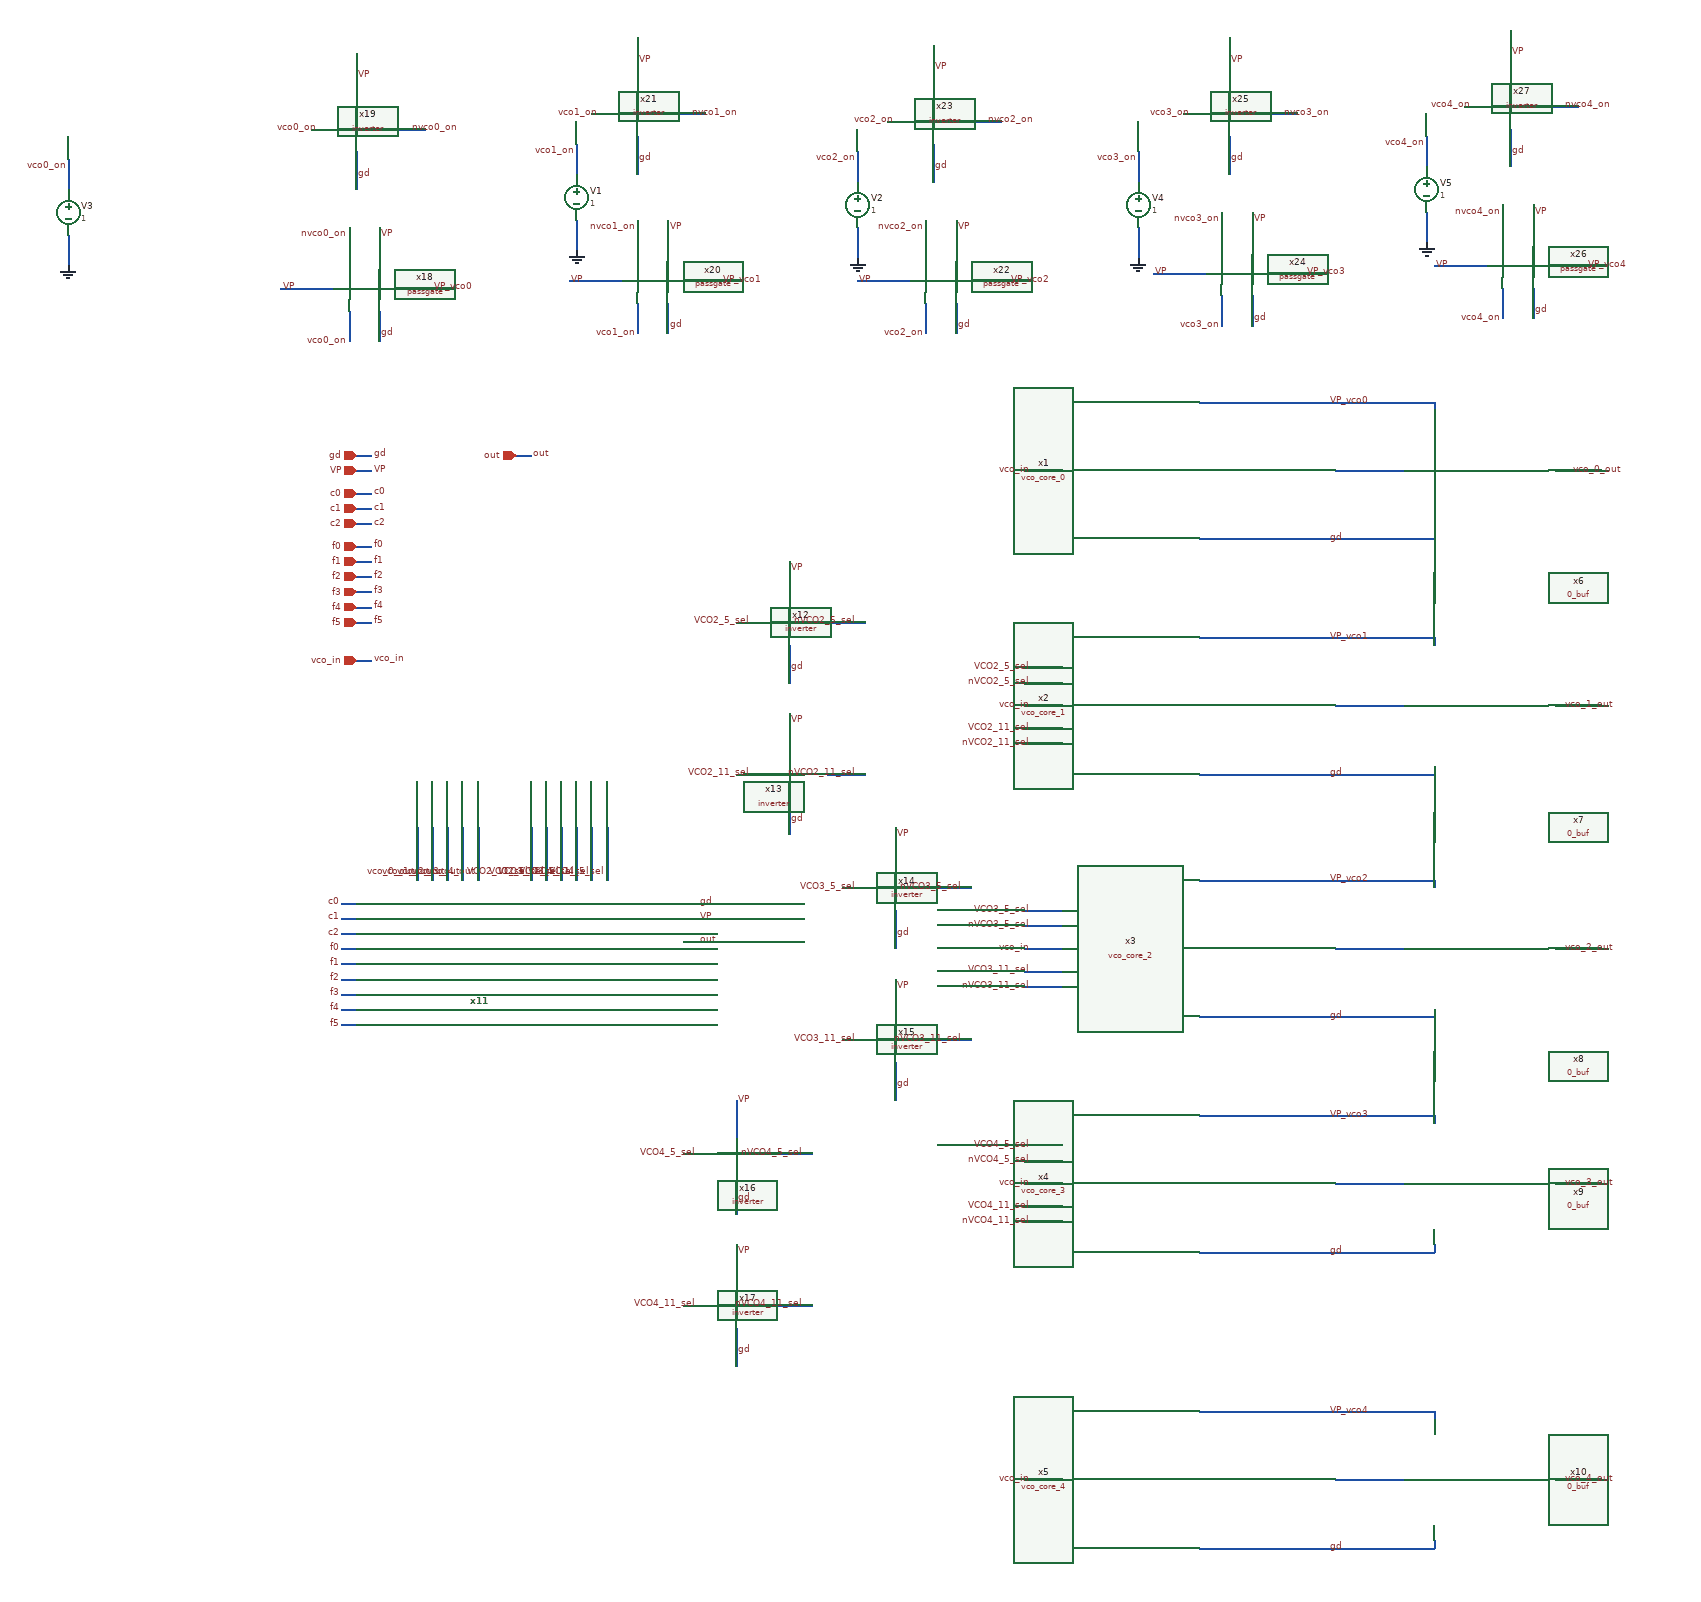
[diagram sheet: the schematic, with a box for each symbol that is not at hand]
v {xschem version=3.4.8RC file_version=1.3}
G {}
K {}
V {}
S {}
F {}
E {}
N 230 -210 320 -210 {lab=#net1}
N 230 100 320 100 {lab=#net2}
N 230 420 320 420 {lab=#net3}
N 230 730 320 730 {lab=#net4}
N 230 1120 320 1120 {lab=#net5}
N 520 -210 580 -210 {lab=vco_0_out}
N 520 100 580 100 {lab=vco_1_out}
N 520 420 580 420 {lab=vco_2_out}
N 520 730 580 730 {lab=vco_3_out}
N 520 1120 580 1120 {lab=vco_4_out}
N -1060 -230 -1040 -230 {lab=gd}
N -1060 -210 -1040 -210 {lab=VP}
N -1060 -160 -1040 -160 {lab=c1}
N -1060 -140 -1040 -140 {lab=c2}
N -1060 -110 -1040 -110 {lab=f0}
N -1060 -90 -1040 -90 {lab=f1}
N -1060 -180 -1040 -180 {lab=c0}
N -1060 -70 -1040 -70 {lab=f2}
N -1060 -50 -1040 -50 {lab=f3}
N -1060 -30 -1040 -30 {lab=f4}
N -1060 -10 -1040 -10 {lab=f5}
N -630 360 -610 360 {lab=gd}
N -630 380 -610 380 {lab=VP}
N -850 -230 -830 -230 {lab=out}
N -630 410 -610 410 {lab=out}
N 50 -120 360 -120 {lab=gd}
N 360 -130 360 -120 {lab=gd}
N 50 190 360 190 {lab=gd}
N 360 180 360 190 {lab=gd}
N 50 510 360 510 {lab=gd}
N 360 500 360 510 {lab=gd}
N 50 820 360 820 {lab=gd}
N 360 810 360 820 {lab=gd}
N 50 1210 360 1210 {lab=gd}
N 360 1200 360 1210 {lab=gd}
N 50 1030 360 1030 {lab=VP_vco4}
N 360 1030 360 1040 {lab=VP_vco4}
N 50 640 360 640 {lab=VP_vco3}
N 360 640 360 650 {lab=VP_vco3}
N 50 330 360 330 {lab=VP_vco2}
N 360 330 360 340 {lab=VP_vco2}
N 50 10 360 10 {lab=VP_vco1}
N 360 10 360 20 {lab=VP_vco1}
N 50 -300 360 -300 {lab=VP_vco0}
N 360 -300 360 -290 {lab=VP_vco0}
N -180 50 -130 50 {lab=VCO2_5_sel}
N -180 130 -130 130 {lab=VCO2_11_sel}
N -180 1120 -130 1120 {lab=vco_in}
N -180 -210 -130 -210 {lab=vco_in}
N -830 260 -830 330 {lab=VCO2_11_sel}
N -810 260 -810 330 {lab=VCO2_5_sel}
N -790 260 -790 330 {lab=VCO3_11_sel}
N -770 260 -770 330 {lab=VCO3_5_sel}
N -750 260 -750 330 {lab=VCO4_11_sel}
N -730 260 -730 330 {lab=VCO4_5_sel}
N -980 260 -980 330 {lab=vco_0_out}
N -960 260 -960 330 {lab=vco_1_out}
N -940 260 -940 330 {lab=vco_2_out}
N -920 260 -920 330 {lab=vco_3_out}
N -900 260 -900 330 {lab=vco_4_out}
N -1080 380 -1060 380 {lab=c1}
N -1080 400 -1060 400 {lab=c2}
N -1080 420 -1060 420 {lab=f0}
N -1080 440 -1060 440 {lab=f1}
N -1080 360 -1060 360 {lab=c0}
N -1080 460 -1060 460 {lab=f2}
N -1080 480 -1060 480 {lab=f3}
N -1080 500 -1060 500 {lab=f4}
N -1080 520 -1060 520 {lab=f5}
N -1060 40 -1040 40 {lab=vco_in}
N -180 100 -130 100 {lab=vco_in}
N -490 -90 -490 -40 {lab=VP}
N -490 20 -490 70 {lab=gd}
N -440 -10 -390 -10 {lab=nVCO2_5_sel}
N -560 -10 -510 -10 {lab=VCO2_5_sel}
N -180 70 -130 70 {lab=nVCO2_5_sel}
N -490 110 -490 160 {lab=VP}
N -490 220 -490 270 {lab=gd}
N -440 190 -390 190 {lab=nVCO2_11_sel}
N -560 190 -510 190 {lab=VCO2_11_sel}
N -180 150 -130 150 {lab=nVCO2_11_sel}
N -180 370 -130 370 {lab=VCO3_5_sel}
N -180 450 -130 450 {lab=VCO3_11_sel}
N -180 420 -130 420 {lab=vco_in}
N -180 390 -130 390 {lab=nVCO3_5_sel}
N -180 470 -130 470 {lab=nVCO3_11_sel}
N -350 260 -350 310 {lab=VP}
N -350 370 -350 420 {lab=gd}
N -300 340 -250 340 {lab=nVCO3_5_sel}
N -420 340 -370 340 {lab=VCO3_5_sel}
N -350 460 -350 510 {lab=VP}
N -350 570 -350 620 {lab=gd}
N -300 540 -250 540 {lab=nVCO3_11_sel}
N -420 540 -370 540 {lab=VCO3_11_sel}
N -180 680 -130 680 {lab=VCO4_5_sel}
N -180 760 -130 760 {lab=VCO4_11_sel}
N -180 730 -130 730 {lab=vco_in}
N -180 700 -130 700 {lab=nVCO4_5_sel}
N -180 780 -130 780 {lab=nVCO4_11_sel}
N -560 720 -560 770 {lab=gd}
N -510 690 -460 690 {lab=nVCO4_5_sel}
N -630 690 -580 690 {lab=VCO4_5_sel}
N -560 810 -560 860 {lab=VP}
N -560 920 -560 970 {lab=gd}
N -510 890 -460 890 {lab=nVCO4_11_sel}
N -630 890 -580 890 {lab=VCO4_11_sel}
N -560 620 -560 670 {lab=VP}
N -1160 -450 -1090 -450 {lab=VP}
N -1010 -450 -930 -450 {lab=VP_vco0}
N -1120 -660 -1080 -660 {lab=vco0_on}
N -1060 -630 -1060 -580 {lab=gd}
N -1060 -760 -1060 -690 {lab=VP}
N -1010 -660 -970 -660 {lab=nvco0_on}
N -1070 -420 -1070 -380 {lab=vco0_on}
N -1070 -530 -1070 -480 {lab=nvco0_on}
N -1030 -530 -1030 -480 {lab=VP}
N -1030 -420 -1030 -380 {lab=gd}
N -780 -460 -710 -460 {lab=VP}
N -630 -460 -550 -460 {lab=VP_vco1}
N -750 -680 -710 -680 {lab=vco1_on}
N -690 -650 -690 -600 {lab=gd}
N -690 -780 -690 -710 {lab=VP}
N -640 -680 -600 -680 {lab=nvco1_on}
N -690 -430 -690 -390 {lab=vco1_on}
N -690 -540 -690 -490 {lab=nvco1_on}
N -650 -540 -650 -490 {lab=VP}
N -650 -430 -650 -390 {lab=gd}
N -400 -460 -330 -460 {lab=VP}
N -250 -460 -170 -460 {lab=VP_vco2}
N -360 -670 -320 -670 {lab=vco2_on}
N -300 -640 -300 -590 {lab=gd}
N -300 -770 -300 -700 {lab=VP}
N -250 -670 -210 -670 {lab=nvco2_on}
N -310 -430 -310 -390 {lab=vco2_on}
N -310 -540 -310 -490 {lab=nvco2_on}
N -270 -540 -270 -490 {lab=VP}
N -270 -430 -270 -390 {lab=gd}
N -10 -470 60 -470 {lab=VP}
N 140 -470 220 -470 {lab=VP_vco3}
N 30 -680 70 -680 {lab=vco3_on}
N 90 -650 90 -600 {lab=gd}
N 90 -780 90 -710 {lab=VP}
N 140 -680 180 -680 {lab=nvco3_on}
N 80 -440 80 -400 {lab=vco3_on}
N 80 -550 80 -500 {lab=nvco3_on}
N 120 -550 120 -500 {lab=VP}
N 120 -440 120 -400 {lab=gd}
N 360 -480 430 -480 {lab=VP}
N 510 -480 590 -480 {lab=VP_vco4}
N 400 -690 440 -690 {lab=vco4_on}
N 460 -660 460 -610 {lab=gd}
N 460 -790 460 -720 {lab=VP}
N 510 -690 550 -690 {lab=nvco4_on}
N 450 -450 450 -410 {lab=vco4_on}
N 450 -560 450 -510 {lab=nvco4_on}
N 490 -560 490 -510 {lab=VP}
N 490 -450 490 -410 {lab=gd}
N -1440 -520 -1440 -480 {lab=0}
N -1440 -620 -1440 -580 {lab=en5}
N -770 -540 -770 -500 {lab=0}
N -770 -640 -770 -600 {lab=en5}
N -400 -530 -400 -490 {lab=0}
N -400 -630 -400 -590 {lab=en5}
N -30 -530 -30 -490 {lab=0}
N -30 -630 -30 -590 {lab=en5}
N 350 -550 350 -510 {lab=0}
N 350 -650 350 -610 {lab=en5}
C {/foss/designs/CHIP-PLL/schematics/vco/vco_cell/vco_core_0.sym} 50 -210 0 0 {name=x1}
C {/foss/designs/CHIP-PLL/schematics/vco/vco_cell/vco_core_1.sym} 50 100 0 0 {name=x2}
C {/foss/designs/CHIP-PLL/schematics/vco/vco_cell/vco_core_2.sym} 50 420 0 0 {name=x3}
C {/foss/designs/CHIP-PLL/schematics/vco/vco_cell/vco_core_3.sym} 50 730 0 0 {name=x4}
C {/foss/designs/CHIP-PLL/schematics/vco/vco_cell/vco_core_4.sym} 50 1120 0 0 {name=x5}
C {/foss/designs/CHIP-PLL/schematics/vco/vco_cell/0_buf.sym} 400 -120 0 0 {name=x6}
C {/foss/designs/CHIP-PLL/schematics/vco/vco_cell/0_buf.sym} 400 190 0 0 {name=x7}
C {/foss/designs/CHIP-PLL/schematics/vco/vco_cell/0_buf.sym} 400 510 0 0 {name=x8}
C {/foss/designs/CHIP-PLL/schematics/vco/vco_cell/0_buf.sym} 400 820 0 0 {name=x9}
C {/foss/designs/CHIP-PLL/schematics/vco/vco_cell/0_buf.sym} 400 1210 0 0 {name=x10}
C {/foss/designs/CHIP-PLL/schematics/divider/schematics/VCO_MUX_and_decoder.sym} -910 490 0 0 {name=x11}
C {iopin.sym} -1060 -230 2 0 {name=p46 lab=gd}
C {lab_wire.sym} -1040 -230 2 0 {name=p53 sig_type=std_logic lab=gd}
C {iopin.sym} -1060 -210 2 0 {name=p54 lab=VP}
C {ipin.sym} -1060 -160 0 0 {name=p2 lab=c1}
C {lab_wire.sym} -1040 -160 2 0 {name=p56 sig_type=std_logic lab=c1}
C {ipin.sym} -1060 -140 0 0 {name=p57 lab=c2}
C {lab_wire.sym} -1040 -140 2 0 {name=p58 sig_type=std_logic lab=c2}
C {ipin.sym} -1060 -110 0 0 {name=p59 lab=f0}
C {lab_wire.sym} -1040 -110 2 0 {name=p60 sig_type=std_logic lab=f0}
C {ipin.sym} -1060 -90 0 0 {name=p61 lab=f1}
C {lab_wire.sym} -1040 -90 2 0 {name=p63 sig_type=std_logic lab=f1}
C {ipin.sym} -1060 -180 0 0 {name=p20 lab=c0}
C {lab_wire.sym} -1040 -180 2 0 {name=p21 sig_type=std_logic lab=c0}
C {lab_wire.sym} -1040 -210 2 0 {name=p1 sig_type=std_logic lab=VP}
C {ipin.sym} -1060 -70 0 0 {name=p19 lab=f2}
C {lab_wire.sym} -1040 -70 2 0 {name=p22 sig_type=std_logic lab=f2}
C {ipin.sym} -1060 -50 0 0 {name=p23 lab=f3}
C {lab_wire.sym} -1040 -50 2 0 {name=p24 sig_type=std_logic lab=f3}
C {ipin.sym} -1060 -30 0 0 {name=p25 lab=f4}
C {lab_wire.sym} -1040 -30 2 0 {name=p26 sig_type=std_logic lab=f4}
C {ipin.sym} -1060 -10 0 0 {name=p27 lab=f5}
C {lab_wire.sym} -1040 -10 2 0 {name=p28 sig_type=std_logic lab=f5}
C {lab_wire.sym} -610 360 2 0 {name=p3 sig_type=std_logic lab=gd}
C {lab_wire.sym} -610 380 2 0 {name=p4 sig_type=std_logic lab=VP}
C {opin.sym} -850 -230 0 1 {name=p55 lab=out}
C {lab_wire.sym} -830 -230 2 0 {name=p62 sig_type=std_logic lab=out}
C {lab_wire.sym} -610 410 2 0 {name=p5 sig_type=std_logic lab=out}
C {lab_wire.sym} 220 10 2 0 {name=p6 sig_type=std_logic lab=VP_vco1}
C {lab_wire.sym} 220 -300 2 0 {name=p7 sig_type=std_logic lab=VP_vco0}
C {lab_wire.sym} 220 330 2 0 {name=p8 sig_type=std_logic lab=VP_vco2}
C {lab_wire.sym} 220 640 2 0 {name=p9 sig_type=std_logic lab=VP_vco3}
C {lab_wire.sym} 220 1030 2 0 {name=p10 sig_type=std_logic lab=VP_vco4}
C {lab_wire.sym} 220 -120 2 0 {name=p11 sig_type=std_logic lab=gd}
C {lab_wire.sym} 220 190 2 0 {name=p12 sig_type=std_logic lab=gd}
C {lab_wire.sym} 220 510 2 0 {name=p13 sig_type=std_logic lab=gd}
C {lab_wire.sym} 220 820 2 0 {name=p14 sig_type=std_logic lab=gd}
C {lab_wire.sym} 220 1210 2 0 {name=p15 sig_type=std_logic lab=gd}
C {lab_wire.sym} -170 130 2 1 {name=p95 sig_type=std_logic lab=VCO2_11_sel}
C {lab_wire.sym} -170 50 2 1 {name=p99 sig_type=std_logic lab=VCO2_5_sel}
C {lab_wire.sym} -830 320 3 1 {name=p33 sig_type=std_logic lab=VCO2_11_sel}
C {lab_wire.sym} -810 320 3 1 {name=p35 sig_type=std_logic lab=VCO2_5_sel}
C {lab_wire.sym} -790 320 3 1 {name=p36 sig_type=std_logic lab=VCO3_11_sel}
C {lab_wire.sym} -770 320 3 1 {name=p37 sig_type=std_logic lab=VCO3_5_sel}
C {lab_wire.sym} -750 320 3 1 {name=p38 sig_type=std_logic lab=VCO4_11_sel}
C {lab_wire.sym} -730 320 3 1 {name=p39 sig_type=std_logic lab=VCO4_5_sel}
C {lab_wire.sym} 540 -210 2 0 {name=p34 sig_type=std_logic lab=vco_0_out}
C {lab_wire.sym} 530 100 2 0 {name=p41 sig_type=std_logic lab=vco_1_out}
C {lab_wire.sym} 530 420 2 0 {name=p42 sig_type=std_logic lab=vco_2_out}
C {lab_wire.sym} 530 730 2 0 {name=p43 sig_type=std_logic lab=vco_3_out}
C {lab_wire.sym} 530 1120 2 0 {name=p44 sig_type=std_logic lab=vco_4_out}
C {lab_wire.sym} -980 320 3 1 {name=p45 sig_type=std_logic lab=vco_0_out}
C {lab_wire.sym} -960 320 3 1 {name=p47 sig_type=std_logic lab=vco_1_out}
C {lab_wire.sym} -940 320 3 1 {name=p48 sig_type=std_logic lab=vco_2_out}
C {lab_wire.sym} -920 320 3 1 {name=p49 sig_type=std_logic lab=vco_3_out}
C {lab_wire.sym} -900 320 3 1 {name=p50 sig_type=std_logic lab=vco_4_out}
C {lab_wire.sym} -1080 380 2 1 {name=p51 sig_type=std_logic lab=c1}
C {lab_wire.sym} -1080 400 2 1 {name=p52 sig_type=std_logic lab=c2}
C {lab_wire.sym} -1080 420 2 1 {name=p64 sig_type=std_logic lab=f0}
C {lab_wire.sym} -1080 440 2 1 {name=p65 sig_type=std_logic lab=f1}
C {lab_wire.sym} -1080 360 2 1 {name=p66 sig_type=std_logic lab=c0}
C {lab_wire.sym} -1080 460 2 1 {name=p67 sig_type=std_logic lab=f2}
C {lab_wire.sym} -1080 480 2 1 {name=p68 sig_type=std_logic lab=f3}
C {lab_wire.sym} -1080 500 2 1 {name=p69 sig_type=std_logic lab=f4}
C {lab_wire.sym} -1080 520 2 1 {name=p70 sig_type=std_logic lab=f5}
C {ipin.sym} -1060 40 0 0 {name=p30 lab=vco_in}
C {lab_wire.sym} -1040 40 2 0 {name=p31 sig_type=std_logic lab=vco_in}
C {lab_wire.sym} -170 -210 2 1 {name=p71 sig_type=std_logic lab=vco_in}
C {lab_wire.sym} -170 100 2 1 {name=p72 sig_type=std_logic lab=vco_in}
C {lab_wire.sym} -170 1120 2 1 {name=p75 sig_type=std_logic lab=vco_in}
C {/foss/designs/CHIP-PLL/schematics/divider/schematics/inverter.sym} -490 -10 0 0 {name=x12}
C {lab_wire.sym} -490 -80 2 0 {name=p32 sig_type=std_logic lab=VP}
C {lab_wire.sym} -490 50 2 0 {name=p40 sig_type=std_logic lab=gd}
C {lab_wire.sym} -540 -10 2 1 {name=p76 sig_type=std_logic lab=VCO2_5_sel}
C {lab_wire.sym} -400 -10 2 1 {name=p77 sig_type=std_logic lab=nVCO2_5_sel}
C {lab_wire.sym} -170 70 2 1 {name=p78 sig_type=std_logic lab=nVCO2_5_sel}
C {/foss/designs/CHIP-PLL/schematics/divider/schematics/inverter.sym} -490 190 0 0 {name=x13}
C {lab_wire.sym} -490 120 2 0 {name=p79 sig_type=std_logic lab=VP}
C {lab_wire.sym} -490 250 2 0 {name=p80 sig_type=std_logic lab=gd}
C {lab_wire.sym} -540 190 2 1 {name=p81 sig_type=std_logic lab=VCO2_11_sel}
C {lab_wire.sym} -400 190 2 1 {name=p82 sig_type=std_logic lab=nVCO2_11_sel}
C {lab_wire.sym} -170 150 2 1 {name=p83 sig_type=std_logic lab=nVCO2_11_sel}
C {lab_wire.sym} -170 450 2 1 {name=p16 sig_type=std_logic lab=VCO3_11_sel}
C {lab_wire.sym} -170 370 2 1 {name=p17 sig_type=std_logic lab=VCO3_5_sel}
C {lab_wire.sym} -170 420 2 1 {name=p18 sig_type=std_logic lab=vco_in}
C {lab_wire.sym} -170 390 2 1 {name=p29 sig_type=std_logic lab=nVCO3_5_sel}
C {lab_wire.sym} -170 470 2 1 {name=p73 sig_type=std_logic lab=nVCO3_11_sel}
C {/foss/designs/CHIP-PLL/schematics/divider/schematics/inverter.sym} -350 340 0 0 {name=x14}
C {lab_wire.sym} -350 270 2 0 {name=p74 sig_type=std_logic lab=VP}
C {lab_wire.sym} -350 400 2 0 {name=p84 sig_type=std_logic lab=gd}
C {lab_wire.sym} -400 340 2 1 {name=p85 sig_type=std_logic lab=VCO3_5_sel}
C {lab_wire.sym} -260 340 2 1 {name=p86 sig_type=std_logic lab=nVCO3_5_sel}
C {/foss/designs/CHIP-PLL/schematics/divider/schematics/inverter.sym} -350 540 0 0 {name=x15}
C {lab_wire.sym} -350 470 2 0 {name=p87 sig_type=std_logic lab=VP}
C {lab_wire.sym} -350 600 2 0 {name=p88 sig_type=std_logic lab=gd}
C {lab_wire.sym} -400 540 2 1 {name=p89 sig_type=std_logic lab=VCO3_11_sel}
C {lab_wire.sym} -260 540 2 1 {name=p90 sig_type=std_logic lab=nVCO3_11_sel}
C {lab_wire.sym} -170 760 2 1 {name=p91 sig_type=std_logic lab=VCO4_11_sel}
C {lab_wire.sym} -170 680 2 1 {name=p92 sig_type=std_logic lab=VCO4_5_sel}
C {lab_wire.sym} -170 730 2 1 {name=p93 sig_type=std_logic lab=vco_in}
C {lab_wire.sym} -170 700 2 1 {name=p94 sig_type=std_logic lab=nVCO4_5_sel}
C {lab_wire.sym} -170 780 2 1 {name=p96 sig_type=std_logic lab=nVCO4_11_sel}
C {/foss/designs/CHIP-PLL/schematics/divider/schematics/inverter.sym} -560 690 0 0 {name=x16}
C {lab_wire.sym} -560 620 2 0 {name=p97 sig_type=std_logic lab=VP}
C {lab_wire.sym} -560 750 2 0 {name=p98 sig_type=std_logic lab=gd}
C {lab_wire.sym} -610 690 2 1 {name=p100 sig_type=std_logic lab=VCO4_5_sel}
C {lab_wire.sym} -470 690 2 1 {name=p101 sig_type=std_logic lab=nVCO4_5_sel}
C {/foss/designs/CHIP-PLL/schematics/divider/schematics/inverter.sym} -560 890 0 0 {name=x17}
C {lab_wire.sym} -560 820 2 0 {name=p102 sig_type=std_logic lab=VP}
C {lab_wire.sym} -560 950 2 0 {name=p103 sig_type=std_logic lab=gd}
C {lab_wire.sym} -610 890 2 1 {name=p104 sig_type=std_logic lab=VCO4_11_sel}
C {lab_wire.sym} -470 890 2 1 {name=p105 sig_type=std_logic lab=nVCO4_11_sel}
C {/foss/designs/CHIP-PLL/schematics/divider/schematics/passgate.sym} -1070 -430 0 0 {name=x18}
C {/foss/designs/CHIP-PLL/schematics/divider/schematics/inverter.sym} -1060 -660 0 0 {name=x19}
C {lab_wire.sym} -1060 -730 2 0 {name=p107 sig_type=std_logic lab=VP}
C {lab_wire.sym} -1060 -600 2 0 {name=p108 sig_type=std_logic lab=gd}
C {lab_wire.sym} -990 -660 2 0 {name=p109 sig_type=std_logic lab=nvco0_on}
C {lab_wire.sym} -1030 -390 2 0 {name=p110 sig_type=std_logic lab=gd}
C {lab_wire.sym} -1030 -520 2 0 {name=p111 sig_type=std_logic lab=VP}
C {lab_wire.sym} -1160 -450 2 0 {name=p112 sig_type=std_logic lab=VP}
C {lab_wire.sym} -960 -450 2 0 {name=p113 sig_type=std_logic lab=VP_vco0}
C {lab_wire.sym} -1070 -380 2 1 {name=p114 sig_type=std_logic lab=vco0_on}
C {lab_wire.sym} -1070 -520 2 1 {name=p115 sig_type=std_logic lab=nvco0_on}
C {/foss/designs/CHIP-PLL/schematics/divider/schematics/passgate.sym} -690 -440 0 0 {name=x20}
C {/foss/designs/CHIP-PLL/schematics/divider/schematics/inverter.sym} -690 -680 0 0 {name=x21}
C {lab_wire.sym} -690 -750 2 0 {name=p117 sig_type=std_logic lab=VP}
C {lab_wire.sym} -690 -620 2 0 {name=p118 sig_type=std_logic lab=gd}
C {lab_wire.sym} -620 -680 2 0 {name=p119 sig_type=std_logic lab=nvco1_on}
C {lab_wire.sym} -650 -400 2 0 {name=p120 sig_type=std_logic lab=gd}
C {lab_wire.sym} -650 -530 2 0 {name=p121 sig_type=std_logic lab=VP}
C {lab_wire.sym} -780 -460 2 0 {name=p122 sig_type=std_logic lab=VP}
C {lab_wire.sym} -580 -460 2 0 {name=p123 sig_type=std_logic lab=VP_vco1}
C {lab_wire.sym} -690 -390 2 1 {name=p124 sig_type=std_logic lab=vco1_on}
C {lab_wire.sym} -690 -530 2 1 {name=p125 sig_type=std_logic lab=nvco1_on}
C {/foss/designs/CHIP-PLL/schematics/divider/schematics/passgate.sym} -310 -440 0 0 {name=x22}
C {/foss/designs/CHIP-PLL/schematics/divider/schematics/inverter.sym} -300 -670 0 0 {name=x23}
C {lab_wire.sym} -300 -740 2 0 {name=p127 sig_type=std_logic lab=VP}
C {lab_wire.sym} -300 -610 2 0 {name=p128 sig_type=std_logic lab=gd}
C {lab_wire.sym} -230 -670 2 0 {name=p129 sig_type=std_logic lab=nvco2_on}
C {lab_wire.sym} -270 -400 2 0 {name=p130 sig_type=std_logic lab=gd}
C {lab_wire.sym} -270 -530 2 0 {name=p131 sig_type=std_logic lab=VP}
C {lab_wire.sym} -400 -460 2 0 {name=p132 sig_type=std_logic lab=VP}
C {lab_wire.sym} -200 -460 2 0 {name=p133 sig_type=std_logic lab=VP_vco2}
C {lab_wire.sym} -310 -390 2 1 {name=p134 sig_type=std_logic lab=vco2_on}
C {lab_wire.sym} -310 -530 2 1 {name=p135 sig_type=std_logic lab=nvco2_on}
C {/foss/designs/CHIP-PLL/schematics/divider/schematics/passgate.sym} 80 -450 0 0 {name=x24}
C {/foss/designs/CHIP-PLL/schematics/divider/schematics/inverter.sym} 90 -680 0 0 {name=x25}
C {lab_wire.sym} 90 -750 2 0 {name=p137 sig_type=std_logic lab=VP}
C {lab_wire.sym} 90 -620 2 0 {name=p138 sig_type=std_logic lab=gd}
C {lab_wire.sym} 160 -680 2 0 {name=p139 sig_type=std_logic lab=nvco3_on}
C {lab_wire.sym} 120 -410 2 0 {name=p140 sig_type=std_logic lab=gd}
C {lab_wire.sym} 120 -540 2 0 {name=p141 sig_type=std_logic lab=VP}
C {lab_wire.sym} -10 -470 2 0 {name=p142 sig_type=std_logic lab=VP}
C {lab_wire.sym} 190 -470 2 0 {name=p143 sig_type=std_logic lab=VP_vco3}
C {lab_wire.sym} 80 -400 2 1 {name=p144 sig_type=std_logic lab=vco3_on}
C {lab_wire.sym} 80 -540 2 1 {name=p145 sig_type=std_logic lab=nvco3_on}
C {/foss/designs/CHIP-PLL/schematics/divider/schematics/passgate.sym} 450 -460 0 0 {name=x26}
C {/foss/designs/CHIP-PLL/schematics/divider/schematics/inverter.sym} 460 -690 0 0 {name=x27}
C {lab_wire.sym} 460 -760 2 0 {name=p147 sig_type=std_logic lab=VP}
C {lab_wire.sym} 460 -630 2 0 {name=p148 sig_type=std_logic lab=gd}
C {lab_wire.sym} 530 -690 2 0 {name=p149 sig_type=std_logic lab=nvco4_on}
C {lab_wire.sym} 490 -420 2 0 {name=p150 sig_type=std_logic lab=gd}
C {lab_wire.sym} 490 -550 2 0 {name=p151 sig_type=std_logic lab=VP}
C {lab_wire.sym} 360 -480 2 0 {name=p152 sig_type=std_logic lab=VP}
C {lab_wire.sym} 560 -480 2 0 {name=p153 sig_type=std_logic lab=VP_vco4}
C {lab_wire.sym} 450 -410 2 1 {name=p154 sig_type=std_logic lab=vco4_on}
C {lab_wire.sym} 450 -550 2 1 {name=p155 sig_type=std_logic lab=nvco4_on}
C {lab_wire.sym} -1110 -660 2 1 {name=p106 sig_type=std_logic lab=vco0_on}
C {lab_wire.sym} -740 -680 2 1 {name=p116 sig_type=std_logic lab=vco1_on}
C {lab_wire.sym} -350 -670 2 1 {name=p126 sig_type=std_logic lab=vco2_on}
C {lab_wire.sym} 40 -680 2 1 {name=p136 sig_type=std_logic lab=vco3_on}
C {lab_wire.sym} 410 -690 2 1 {name=p146 sig_type=std_logic lab=vco4_on}
C {vsource.sym} -1440 -550 0 0 {name=V3 value=1 savecurrent=false}
C {gnd.sym} -1440 -480 0 0 {name=l1 lab=0
}
C {lab_wire.sym} -1440 -610 2 1 {name=p156 sig_type=std_logic lab=vco0_on}
C {vsource.sym} -770 -570 0 0 {name=V1 value=1 savecurrent=false}
C {gnd.sym} -770 -500 0 0 {name=l2 lab=0
}
C {lab_wire.sym} -770 -630 2 1 {name=p157 sig_type=std_logic lab=vco1_on}
C {vsource.sym} -400 -560 0 0 {name=V2 value=1 savecurrent=false}
C {gnd.sym} -400 -490 0 0 {name=l3 lab=0
}
C {lab_wire.sym} -400 -620 2 1 {name=p158 sig_type=std_logic lab=vco2_on}
C {vsource.sym} -30 -560 0 0 {name=V4 value=1 savecurrent=false}
C {gnd.sym} -30 -490 0 0 {name=l4 lab=0
}
C {lab_wire.sym} -30 -620 2 1 {name=p159 sig_type=std_logic lab=vco3_on}
C {vsource.sym} 350 -580 0 0 {name=V5 value=1 savecurrent=false}
C {gnd.sym} 350 -510 0 0 {name=l5 lab=0
}
C {lab_wire.sym} 350 -640 2 1 {name=p160 sig_type=std_logic lab=vco4_on}
